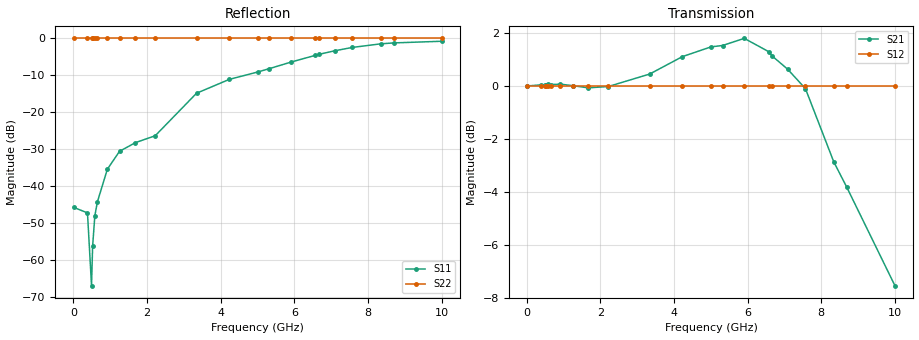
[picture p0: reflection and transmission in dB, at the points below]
! Texas Instruments, Inc.
! ADC12DJ5200RF - CH B S-Parameters (Dual Ch Mode, Fs = 5.2 GSPS, 25 degC case, 37 degC juntion)
! Port 1 represents the 100-ohm differenal input, Port 2 the digital output
! freq  dbS11  angS11  dbS21 angS21 dbS12 angS12 dbS22 angS22
# HZ S DB R 100
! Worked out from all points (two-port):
!   1000 points, 10 MHz to 10 GHz, reference 100 ohm
!   highest |S21| = 1.80 dB at 5.91 GHz (marker M1); lowest = -7.6 dB at 10 GHz (marker M2)
!   |S21| within 3 dB of the highest: start of sweep to 7.927 GHz
!   lowest |S11| = -66.8 dB at 490 MHz (marker M3), VSWR 1.00, Z = 100 + j0.0909 ohm
!   |S11| at or under -10 dB: start of sweep to 4.655 GHz
!   |S22| runs from 0.0 to 0.0 dB; largest |S21 - S12| = 0.81
!   S11 on the Smith chart (normalised r, x): 10 MHz: 1.01, -0.00; 5.32 GHz: 0.44, +0.07; 6.57 GHz: 0.53, +0.96; 7.57 GHz: 2.79, +3.39; 8.69 GHz: 0.87, -3.26; 10 GHz: 0.11, -1.18
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1e7  -45.69 -2.8  0.00 0.0  0.00 0.0  0.00 0.0
3.8e8  -47.17 -16.4  0.04 -0.2  0.00 0.0  0.00 0.0
4.9e8  -66.84 93.5  0.04 -0.3  0.00 0.0  0.00 0.0
5.2e8  -56.15 -177.4  0.05 -0.3  0.00 0.0  0.00 0.0
5.8e8  -47.93 -158.5  0.06 -0.3  0.00 0.0  0.00 0.0
6.5e8  -44.16 -162.0  0.05 -0.4  0.00 0.0  0.00 0.0
9.2e8  -35.36 -172.3  0.07 -0.6  0.00 0.0  0.00 0.0
1.25e9  -30.53 -174.5  0.01 -1.0  0.00 0.0  0.00 0.0
1.68e9  -28.19 -167.0  -0.07 -0.7  0.00 0.0  0.00 0.0
2.22e9  -26.31 -127.8  -0.02 -0.2  0.00 0.0  0.00 0.0
3.34e9  -14.84 -101.2  0.45 0.6  0.00 0.0  0.00 0.0
4.23e9  -11.08 -126.9  1.11 -1.3  0.00 0.0  0.00 0.0
5.01e9  -9.07 -169.7  1.48 -7.2  0.00 0.0  0.00 0.0
5.32e9  -8.17 169.9  1.53 -9.0  0.00 0.0  0.00 0.0
5.91e9  -6.40 129.7  1.80 -16.0  0.00 0.0  0.00 0.0
6.57e9  -4.57 84.1  1.30 -27.1  0.00 0.0  0.00 0.0
6.67e9  -4.31 77.3  1.13 -28.5  0.00 0.0  0.00 0.0
7.09e9  -3.36 49.3  0.63 -33.3  0.00 0.0  0.00 0.0
7.57e9  -2.45 20.4  -0.10 -41.3  0.00 0.0  0.00 0.0
8.34e9  -1.48 -18.1  -2.87 -49.6  0.00 0.0  0.00 0.0
8.69e9  -1.23 -32.1  -3.82 -48.4  0.00 0.0  0.00 0.0
1e10  -0.78 -80.5  -7.55 -51.4  0.00 0.0  0.00 0.0
